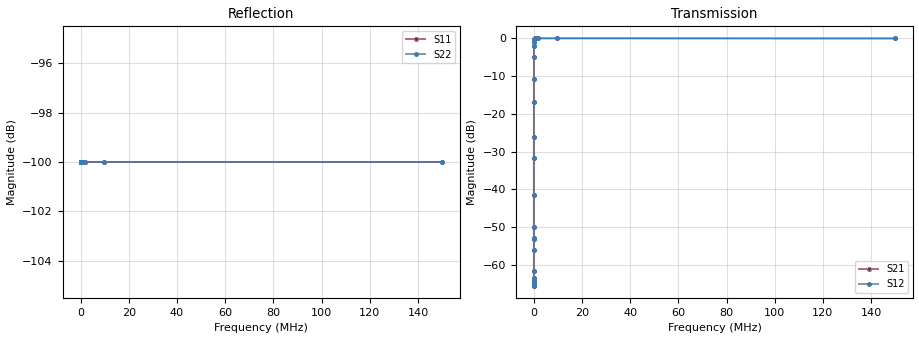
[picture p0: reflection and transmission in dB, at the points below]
! 4/24/2024 2:05 PM
! H:\MS4647B\Prototype_Data\amotech 110G\LF_ground with bigger hole.s2p
! CORRECTED DATA
# Hz S DB R 50.0
! FREQ  S11DB  S11A  S21DB  S21A  S12DB  S12A  S22DB  S22A
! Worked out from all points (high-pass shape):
!   401 points, 10 Hz to 150 MHz, reference 50 ohm
!   highest |S21| = -0.01 dB at 1.662 MHz (marker M1); lowest = -65.5 dB at 13.92 Hz (marker M2)
!   |S21| within 3 dB of the highest: 18.05 kHz to end of sweep
!   lowest |S11| = -100.0 dB at 10 Hz (marker M3), VSWR 1.00, Z = 50 + j0 ohm
!   |S11| at or under -10 dB: start of sweep to end of sweep
!   |S22| runs from -100.0 to -100.0 dB; largest |S21 - S12| = 0
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10  -100.00 0.0  -64.33 -64.3  -64.33 -64.3  -100.00 0.0
11.79671  -100.00 0.0  -63.43 -63.4  -63.43 -63.4  -100.00 0.0
13.91624  -100.00 0.0  -65.47 -65.5  -65.47 -65.5  -100.00 0.0
15.1148  -100.00 0.0  -64.76 -64.8  -64.76 -64.8  -100.00 0.0
17.83049  -100.00 0.0  -61.59 -61.6  -61.59 -61.6  -100.00 0.0
34.53082  -100.00 0.0  -55.90 -55.9  -55.90 -55.9  -100.00 0.0
42.45296  -100.00 0.0  -53.24 -53.2  -53.24 -53.2  -100.00 0.0
48.0539  -100.00 0.0  -52.95 -52.9  -52.95 -52.9  -100.00 0.0
59.07855  -100.00 0.0  -49.93 -49.9  -49.93 -49.9  -100.00 0.0
159.2191  -100.00 0.0  -41.39 -41.4  -41.39 -41.4  -100.00 0.0
485.7149  -100.00 0.0  -31.71 -31.7  -31.71 -31.7  -100.00 0.0
831.0065  -100.00 0.0  -26.22 -26.2  -26.22 -26.2  -100.00 0.0
2535.074  -100.00 0.0  -16.72 -16.7  -16.72 -16.7  -100.00 0.0
5332.301  -100.00 0.0  -10.72 -10.7  -10.72 -10.7  -100.00 0.0
12182.02  -100.00 0.0  -4.91 -4.9  -4.91 -4.9  -100.00 0.0
23591.9  -100.00 0.0  -2.04 -2.0  -2.04 -2.0  -100.00 0.0
40363.22  -100.00 0.0  -0.88 -0.9  -0.88 -0.9  -100.00 0.0
96101.61  -100.00 0.0  -0.20 -0.2  -0.20 -0.2  -100.00 0.0
616653.1  -100.00 0.0  -0.01 -0.0  -0.01 -0.0  -100.00 0.0
1661906  -100.00 0.0  -0.01 -0.0  -0.01 -0.0  -100.00 0.0
9818298  -100.00 0.0  -0.01 -0.0  -0.01 -0.0  -100.00 0.0
1.5e8  -100.00 0.0  -0.04 -0.0  -0.04 -0.0  -100.00 0.0
